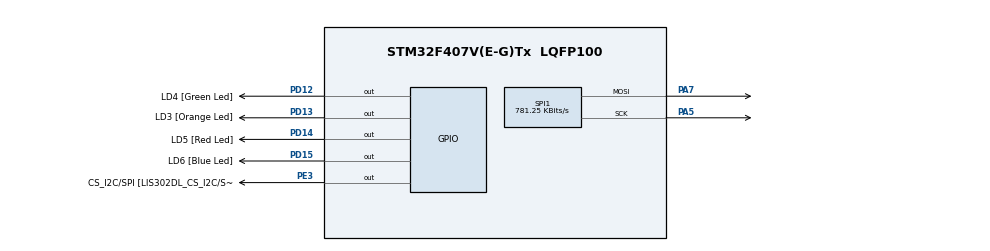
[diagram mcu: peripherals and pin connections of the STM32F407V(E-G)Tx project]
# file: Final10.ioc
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Mcu.Family=STM32F4
Mcu.Name=STM32F407V(E-G)Tx
Mcu.Package=LQFP100
NVIC.PriorityGroup=NVIC_PRIORITYGROUP_0
PA13.Mode=Serial_Wire
PA13.Signal=SYS_JTMS-SWDIO
PA14.Mode=Serial_Wire
PA14.Signal=SYS_JTCK-SWCLK
PA5.Mode=TX_Only_Simplex_Unidirect_Master
PA5.Signal=SPI1_SCK
PA7.Mode=TX_Only_Simplex_Unidirect_Master
PA7.Signal=SPI1_MOSI
PC14-OSC32_IN.Mode=LSE-External-Oscillator
PC14-OSC32_IN.Signal=RCC_OSC32_IN
PC15-OSC32_OUT.Mode=LSE-External-Oscillator
PC15-OSC32_OUT.Signal=RCC_OSC32_OUT
PD12.GPIO_Label=LD4 [Green Led]
PD12.GPIO_PuPd=GPIO_NOPULL
PD12.GPIO_Speed=GPIO_SPEED_FREQ_LOW
PD12.Signal=GPIO_Output
PD13.GPIO_Label=LD3 [Orange Led]
PD13.GPIO_PuPd=GPIO_NOPULL
PD13.GPIO_Speed=GPIO_SPEED_FREQ_LOW
PD13.Signal=GPIO_Output
PD14.GPIO_Label=LD5 [Red Led]
PD14.GPIO_PuPd=GPIO_NOPULL
PD14.GPIO_Speed=GPIO_SPEED_FREQ_LOW
PD14.Signal=GPIO_Output
PD15.GPIO_Label=LD6 [Blue Led]
PD15.GPIO_PuPd=GPIO_NOPULL
PD15.GPIO_Speed=GPIO_SPEED_FREQ_LOW
PD15.Signal=GPIO_Output
PE3.GPIO_Label=CS_I2C/SPI [LIS302DL_CS_I2C/SPI]
PE3.GPIO_PuPd=GPIO_NOPULL
PE3.GPIO_Speed=GPIO_SPEED_FREQ_HIGH
PE3.PinState=GPIO_PIN_SET
PE3.Signal=GPIO_Output
ProjectManager.HeapSize=0x200
ProjectManager.StackSize=0x400
ProjectManager.TargetToolchain=MDK-ARM V5.27
RCC.48MHZClocksFreq_Value=14285714.285714285
RCC.AHBFreq_Value=25000000
RCC.APB1CLKDivider=RCC_HCLK_DIV4
RCC.APB1Freq_Value=6250000
RCC.APB1TimFreq_Value=12500000
RCC.APB2CLKDivider=RCC_HCLK_DIV2
RCC.APB2Freq_Value=12500000
RCC.APB2TimFreq_Value=25000000
RCC.CortexFreq_Value=25000000
RCC.HCLKFreq_Value=25000000
RCC.HSE_VALUE=8000000
RCC.HSI_VALUE=16000000
RCC.PLLM=8
RCC.PLLN=50
RCC.PLLP=RCC_PLLP_DIV4
RCC.PLLQ=7
RCC.SYSCLKFreq_VALUE=25000000
RCC.SYSCLKSource=RCC_SYSCLKSOURCE_PLLCLK
RCC.VCOOutputFreq_Value=100000000
SPI1.BaudRatePrescaler=SPI_BAUDRATEPRESCALER_16
SPI1.CLKPolarity=SPI_POLARITY_HIGH
SPI1.CalculateBaudRate=781.25 KBits/s
SPI1.DataSize=SPI_DATASIZE_16BIT
SPI1.Direction=SPI_DIRECTION_2LINES
SPI1.FirstBit=SPI_FIRSTBIT_MSB
SPI1.Mode=SPI_MODE_MASTER
SPI1.VirtualType=VM_MASTER
board=STM32F407G-DISC1

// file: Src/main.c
/* USER CODE BEGIN Header */
/**
  ******************************************************************************
  * @file           : main.c
  * @brief          : Main program body
  ******************************************************************************
  * @attention
  *
  * <h2><center>&copy; Copyright (c) 2021 STMicroelectronics.
  * All rights reserved.</center></h2>
  *
  * This software component is licensed by ST under BSD 3-Clause license,
  * the "License"; You may not use this file except in compliance with the
  * License. You may obtain a copy of the License at:
  *                        opensource.org/licenses/BSD-3-Clause
  *
  ******************************************************************************
  */
/* USER CODE END Header */
#include "main.h"
#include "Speed_Motor.h"
#include "Init_7seg.h"
#include "Display_7seg.h"
#include "Height_Angle_Motor.h"
#include "Write_Read_Flash.h"
#include "Saving_Function.h"
#include "Set_Origin.h"

SPI_HandleTypeDef hspi1;

uint32_t address_height=0x080E0000;
uint32_t address_angle=0x080E0002;
signed int IT_counter_angle;
signed int IT_counter_hight;
int saving_index=0;
int saving_loop=50000;
int saving_flage=0;

void SystemClock_Config(void);
static void MX_GPIO_Init(void);
static void MX_SPI1_Init(void);

int main(void)
{

  /* MCU Configuration--------------------------------------------------------*/

  /* Reset of all peripherals, Initializes the Flash interface and the Systick. */
  HAL_Init();

  /* Configure the system clock */
  SystemClock_Config();

  /* Initialize all configured peripherals */
  MX_GPIO_Init();
	MX_SPI1_Init();
  /* USER CODE BEGIN 2 */
 	display_init();

	read_data();

	display_number( IT_counter_hight, IT_counter_angle);

  /* USER CODE END 2 */

  /* Infinite loop */
  while (1)
  {

    /* USER CODE BEGIN 3 */
		speed_level();
		height_increasing();
		height_decreasing();
		angle_increasing();
		angle_decreasing();
		Saving_Routin();
		set_origin();

  }
  /* USER CODE END 3 */
}

void SystemClock_Config(void)
{
  RCC_OscInitTypeDef RCC_OscInitStruct = {0};
  RCC_ClkInitTypeDef RCC_ClkInitStruct = {0};

  /** Configure the main internal regulator output voltage
  */
  __HAL_RCC_PWR_CLK_ENABLE();
  __HAL_PWR_VOLTAGESCALING_CONFIG(PWR_REGULATOR_VOLTAGE_SCALE1);
  /** Initializes the RCC Oscillators according to the specified parameters
  * in the RCC_OscInitTypeDef structure.
  */
  RCC_OscInitStruct.OscillatorType = RCC_OSCILLATORTYPE_HSE;
  RCC_OscInitStruct.HSEState = RCC_HSE_ON;
  RCC_OscInitStruct.PLL.PLLState = RCC_PLL_NONE;
  if (HAL_RCC_OscConfig(&RCC_OscInitStruct) != HAL_OK)
  {
    Error_Handler();
  }
  /** Initializes the CPU, AHB and APB buses clocks
  */
  RCC_ClkInitStruct.ClockType = RCC_CLOCKTYPE_HCLK|RCC_CLOCKTYPE_SYSCLK
                              |RCC_CLOCKTYPE_PCLK1|RCC_CLOCKTYPE_PCLK2;
  RCC_ClkInitStruct.SYSCLKSource = RCC_SYSCLKSOURCE_HSE;
  RCC_ClkInitStruct.AHBCLKDivider = RCC_SYSCLK_DIV1;
  RCC_ClkInitStruct.APB1CLKDivider = RCC_HCLK_DIV1;
  RCC_ClkInitStruct.APB2CLKDivider = RCC_HCLK_DIV1;

  if (HAL_RCC_ClockConfig(&RCC_ClkInitStruct, FLASH_LATENCY_0) != HAL_OK)
  {
    Error_Handler();
  }
  /** Enables the Clock Security System
  */
  HAL_RCC_EnableCSS();
}

static void MX_SPI1_Init(void)
{

  /* SPI1 parameter configuration*/
  hspi1.Instance = SPI1;
  hspi1.Init.Mode = SPI_MODE_MASTER;
  hspi1.Init.Direction = SPI_DIRECTION_2LINES;
  hspi1.Init.DataSize = SPI_DATASIZE_16BIT;
  hspi1.Init.CLKPolarity = SPI_POLARITY_HIGH;
  hspi1.Init.CLKPhase = SPI_PHASE_1EDGE;
  hspi1.Init.NSS = SPI_NSS_SOFT;
  hspi1.Init.BaudRatePrescaler = SPI_BAUDRATEPRESCALER_2;
  hspi1.Init.FirstBit = SPI_FIRSTBIT_MSB;
  hspi1.Init.TIMode = SPI_TIMODE_DISABLE;
  hspi1.Init.CRCCalculation = SPI_CRCCALCULATION_DISABLE;
  hspi1.Init.CRCPolynomial = 10;
  if (HAL_SPI_Init(&hspi1) != HAL_OK)
  {
    Error_Handler();
  }

}

 static void MX_GPIO_Init(void)
{
  GPIO_InitTypeDef GPIO_InitStruct = {0};

  /* GPIO Ports Clock Enable */
  __HAL_RCC_GPIOE_CLK_ENABLE();
  __HAL_RCC_GPIOC_CLK_ENABLE();
  __HAL_RCC_GPIOA_CLK_ENABLE();
  __HAL_RCC_GPIOB_CLK_ENABLE();
  __HAL_RCC_GPIOD_CLK_ENABLE();

	/* EXTI interrupt init (Interupt)*/
  HAL_NVIC_SetPriority(EXTI1_IRQn, 1, 1);
  HAL_NVIC_EnableIRQ(EXTI1_IRQn);
  //HAL_NVIC_SetPriority(EXTI2_IRQn, 0, 0);
  //HAL_NVIC_EnableIRQ(EXTI2_IRQn);
  HAL_NVIC_SetPriority(EXTI3_IRQn, 2, 2);
  HAL_NVIC_EnableIRQ(EXTI3_IRQn);
  //HAL_NVIC_SetPriority(EXTI4_IRQn, 0, 0);
  //HAL_NVIC_EnableIRQ(EXTI4_IRQn);

  /*Configure GPIO pin Output Level (SPI_pins)*/
  HAL_GPIO_WritePin(CS_I2C_SPI_GPIO_Port, CS_I2C_SPI_Pin, GPIO_PIN_SET);
  /*Configure GPIO pin : CS_I2C_SPI_Pin */
  GPIO_InitStruct.Pin = CS_I2C_SPI_Pin;
  GPIO_InitStruct.Mode = GPIO_MODE_OUTPUT_PP;
  GPIO_InitStruct.Pull = GPIO_NOPULL;
  GPIO_InitStruct.Speed = GPIO_SPEED_FREQ_HIGH;
  HAL_GPIO_Init(CS_I2C_SPI_GPIO_Port, &GPIO_InitStruct);

	/*Configure GPIO pin input Level (UP/Down keys)*/
	HAL_GPIO_ReadPin(GPIOC, GPIO_PIN_6 | GPIO_PIN_7 | GPIO_PIN_8 | GPIO_PIN_9);
	/*Configure GPIO pins : PC6 PC7 PC8 PC9 */
  GPIO_InitStruct.Pin = GPIO_PIN_6|GPIO_PIN_7|GPIO_PIN_8|GPIO_PIN_9;
  GPIO_InitStruct.Mode = GPIO_MODE_INPUT;
  GPIO_InitStruct.Pull = GPIO_PULLUP;
  HAL_GPIO_Init(GPIOC, &GPIO_InitStruct);

	/*Configure GPIO pin Output Level (speed_LED_PA0=5000;PA6=4000; PB0=3000)*/
  HAL_GPIO_WritePin(GPIOA, GPIO_PIN_0|GPIO_PIN_6, GPIO_PIN_RESET);
	/*Configure GPIO pins : PA0 PA6 */
  GPIO_InitStruct.Pin = GPIO_PIN_0|GPIO_PIN_6;
  GPIO_InitStruct.Mode = GPIO_MODE_OUTPUT_PP;
  GPIO_InitStruct.Pull = GPIO_PULLDOWN;
  GPIO_InitStruct.Speed = GPIO_SPEED_FREQ_LOW;
  HAL_GPIO_Init(GPIOA, &GPIO_InitStruct);

	/*Configure GPIO pin Output Level (speed_LED_PB0=3000)*/
  HAL_GPIO_WritePin(GPIOB, GPIO_PIN_0, GPIO_PIN_RESET);
	/*Configure GPIO pins : PB0 */
  GPIO_InitStruct.Pin = GPIO_PIN_0;
  GPIO_InitStruct.Mode = GPIO_MODE_OUTPUT_PP;
  GPIO_InitStruct.Pull = GPIO_PULLDOWN;
  GPIO_InitStruct.Speed = GPIO_SPEED_FREQ_LOW;
  HAL_GPIO_Init(GPIOB, &GPIO_InitStruct);

	/*Configure GPIO pin input Level (Set_Zero_Level)*/
	HAL_GPIO_ReadPin(GPIOA, GPIO_PIN_6);
	/*Configure GPIO pins : PA2 */
  GPIO_InitStruct.Pin = GPIO_PIN_2;
  GPIO_InitStruct.Mode = GPIO_MODE_INPUT;
  GPIO_InitStruct.Pull = GPIO_PULLUP;
  HAL_GPIO_Init(GPIOA, &GPIO_InitStruct);

	/*Configure GPIO pins : PA1 PA3 (sensors) */
  GPIO_InitStruct.Pin = GPIO_PIN_1|GPIO_PIN_3;
  GPIO_InitStruct.Mode = GPIO_MODE_IT_FALLING;
  GPIO_InitStruct.Pull = GPIO_PULLUP;
  HAL_GPIO_Init(GPIOA, &GPIO_InitStruct);

	/*Configure GPIO pin Output Level (on_off relay) */
  HAL_GPIO_WritePin(GPIOB, GPIO_PIN_7|GPIO_PIN_8|GPIO_PIN_9|GPIO_PIN_10, GPIO_PIN_RESET);
  /*Configure GPIO pins :  PB7 PB8 PB9 PB10 */
  GPIO_InitStruct.Pin = GPIO_PIN_7|GPIO_PIN_8|GPIO_PIN_9|GPIO_PIN_10;
  GPIO_InitStruct.Mode = GPIO_MODE_OUTPUT_PP;
  GPIO_InitStruct.Pull = GPIO_PULLDOWN;
  GPIO_InitStruct.Speed = GPIO_SPEED_FREQ_LOW;
  HAL_GPIO_Init(GPIOB, &GPIO_InitStruct);

	/*Configure GPIO pin input Level (speed_keys)*/
	//HAL_GPIO_ReadPin(GPIOA, GPIO_PIN_8|GPIO_PIN_9);
  /*Configure GPIO pins : PA8 PA9 */
  GPIO_InitStruct.Pin = GPIO_PIN_8|GPIO_PIN_9;
  GPIO_InitStruct.Mode = GPIO_MODE_INPUT;
  GPIO_InitStruct.Pull = GPIO_PULLUP;
  HAL_GPIO_Init(GPIOA, &GPIO_InitStruct);

}

void Error_Handler(void)
{
  __disable_irq();
  while (1)
  {
  }
}

/************************ (C) COPYRIGHT STMicroelectronics *****END OF FILE****/
